# Generated by FakeRAM 2.0
VERSION 5.7 ;
BUSBITCHARS "[]" ;
PROPERTYDEFINITIONS
  MACRO width INTEGER ;
  MACRO depth INTEGER ;
  MACRO banks INTEGER ;
END PROPERTYDEFINITIONS
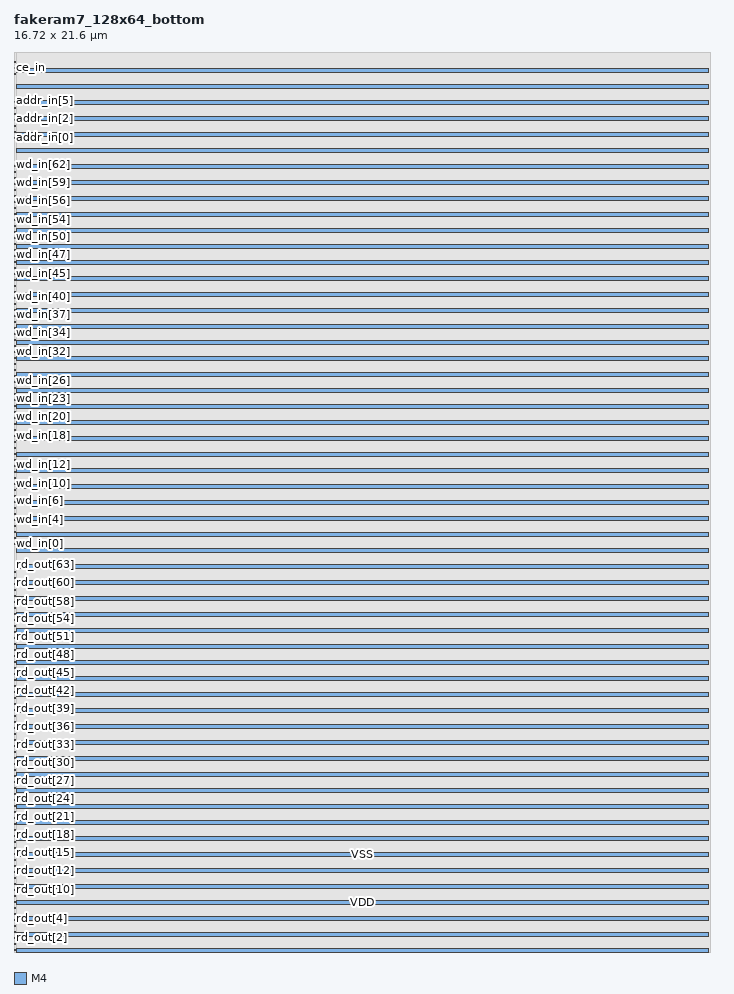
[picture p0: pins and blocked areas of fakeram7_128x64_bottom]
MACRO fakeram7_128x64_bottom
  PROPERTY width 64 ;
  PROPERTY depth 128 ;
  PROPERTY banks 2 ;
  FOREIGN fakeram7_128x64_bottom 0 0 ;
  SYMMETRY X Y R90 ;
  SIZE 16.720 BY 21.600 ;
  CLASS BLOCK ;
  PIN rd_out[0]
    DIRECTION OUTPUT ;
    USE SIGNAL ;
    SHAPE ABUTMENT ;
    PORT
      LAYER M4 ;
      RECT 0.000 0.039 0.024 0.063 ;
    END
  END rd_out[0]
  PIN rd_out[1]
    DIRECTION OUTPUT ;
    USE SIGNAL ;
    SHAPE ABUTMENT ;
    PORT
      LAYER M4 ;
      RECT 0.000 0.183 0.024 0.207 ;
    END
  END rd_out[1]
  PIN rd_out[2]
    DIRECTION OUTPUT ;
    USE SIGNAL ;
    SHAPE ABUTMENT ;
    PORT
      LAYER M4 ;
      RECT 0.000 0.327 0.024 0.351 ;
    END
  END rd_out[2]
  PIN rd_out[3]
    DIRECTION OUTPUT ;
    USE SIGNAL ;
    SHAPE ABUTMENT ;
    PORT
      LAYER M4 ;
      RECT 0.000 0.471 0.024 0.495 ;
    END
  END rd_out[3]
  PIN rd_out[4]
    DIRECTION OUTPUT ;
    USE SIGNAL ;
    SHAPE ABUTMENT ;
    PORT
      LAYER M4 ;
      RECT 0.000 0.615 0.024 0.639 ;
    END
  END rd_out[4]
  PIN rd_out[5]
    DIRECTION OUTPUT ;
    USE SIGNAL ;
    SHAPE ABUTMENT ;
    PORT
      LAYER M4 ;
      RECT 0.000 0.759 0.024 0.783 ;
    END
  END rd_out[5]
  PIN rd_out[6]
    DIRECTION OUTPUT ;
    USE SIGNAL ;
    SHAPE ABUTMENT ;
    PORT
      LAYER M4 ;
      RECT 0.000 0.903 0.024 0.927 ;
    END
  END rd_out[6]
  PIN rd_out[7]
    DIRECTION OUTPUT ;
    USE SIGNAL ;
    SHAPE ABUTMENT ;
    PORT
      LAYER M4 ;
      RECT 0.000 1.047 0.024 1.071 ;
    END
  END rd_out[7]
  PIN rd_out[8]
    DIRECTION OUTPUT ;
    USE SIGNAL ;
    SHAPE ABUTMENT ;
    PORT
      LAYER M4 ;
      RECT 0.000 1.191 0.024 1.215 ;
    END
  END rd_out[8]
  PIN rd_out[9]
    DIRECTION OUTPUT ;
    USE SIGNAL ;
    SHAPE ABUTMENT ;
    PORT
      LAYER M4 ;
      RECT 0.000 1.335 0.024 1.359 ;
    END
  END rd_out[9]
  PIN rd_out[10]
    DIRECTION OUTPUT ;
    USE SIGNAL ;
    SHAPE ABUTMENT ;
    PORT
      LAYER M4 ;
      RECT 0.000 1.479 0.024 1.503 ;
    END
  END rd_out[10]
  PIN rd_out[11]
    DIRECTION OUTPUT ;
    USE SIGNAL ;
    SHAPE ABUTMENT ;
    PORT
      LAYER M4 ;
      RECT 0.000 1.623 0.024 1.647 ;
    END
  END rd_out[11]
  PIN rd_out[12]
    DIRECTION OUTPUT ;
    USE SIGNAL ;
    SHAPE ABUTMENT ;
    PORT
      LAYER M4 ;
      RECT 0.000 1.767 0.024 1.791 ;
    END
  END rd_out[12]
  PIN rd_out[13]
    DIRECTION OUTPUT ;
    USE SIGNAL ;
    SHAPE ABUTMENT ;
    PORT
      LAYER M4 ;
      RECT 0.000 1.911 0.024 1.935 ;
    END
  END rd_out[13]
  PIN rd_out[14]
    DIRECTION OUTPUT ;
    USE SIGNAL ;
    SHAPE ABUTMENT ;
    PORT
      LAYER M4 ;
      RECT 0.000 2.055 0.024 2.079 ;
    END
  END rd_out[14]
  PIN rd_out[15]
    DIRECTION OUTPUT ;
    USE SIGNAL ;
    SHAPE ABUTMENT ;
    PORT
      LAYER M4 ;
      RECT 0.000 2.199 0.024 2.223 ;
    END
  END rd_out[15]
  PIN rd_out[16]
    DIRECTION OUTPUT ;
    USE SIGNAL ;
    SHAPE ABUTMENT ;
    PORT
      LAYER M4 ;
      RECT 0.000 2.343 0.024 2.367 ;
    END
  END rd_out[16]
  PIN rd_out[17]
    DIRECTION OUTPUT ;
    USE SIGNAL ;
    SHAPE ABUTMENT ;
    PORT
      LAYER M4 ;
      RECT 0.000 2.487 0.024 2.511 ;
    END
  END rd_out[17]
  PIN rd_out[18]
    DIRECTION OUTPUT ;
    USE SIGNAL ;
    SHAPE ABUTMENT ;
    PORT
      LAYER M4 ;
      RECT 0.000 2.631 0.024 2.655 ;
    END
  END rd_out[18]
  PIN rd_out[19]
    DIRECTION OUTPUT ;
    USE SIGNAL ;
    SHAPE ABUTMENT ;
    PORT
      LAYER M4 ;
      RECT 0.000 2.775 0.024 2.799 ;
    END
  END rd_out[19]
  PIN rd_out[20]
    DIRECTION OUTPUT ;
    USE SIGNAL ;
    SHAPE ABUTMENT ;
    PORT
      LAYER M4 ;
      RECT 0.000 2.919 0.024 2.943 ;
    END
  END rd_out[20]
  PIN rd_out[21]
    DIRECTION OUTPUT ;
    USE SIGNAL ;
    SHAPE ABUTMENT ;
    PORT
      LAYER M4 ;
      RECT 0.000 3.063 0.024 3.087 ;
    END
  END rd_out[21]
  PIN rd_out[22]
    DIRECTION OUTPUT ;
    USE SIGNAL ;
    SHAPE ABUTMENT ;
    PORT
      LAYER M4 ;
      RECT 0.000 3.207 0.024 3.231 ;
    END
  END rd_out[22]
  PIN rd_out[23]
    DIRECTION OUTPUT ;
    USE SIGNAL ;
    SHAPE ABUTMENT ;
    PORT
      LAYER M4 ;
      RECT 0.000 3.351 0.024 3.375 ;
    END
  END rd_out[23]
  PIN rd_out[24]
    DIRECTION OUTPUT ;
    USE SIGNAL ;
    SHAPE ABUTMENT ;
    PORT
      LAYER M4 ;
      RECT 0.000 3.495 0.024 3.519 ;
    END
  END rd_out[24]
  PIN rd_out[25]
    DIRECTION OUTPUT ;
    USE SIGNAL ;
    SHAPE ABUTMENT ;
    PORT
      LAYER M4 ;
      RECT 0.000 3.639 0.024 3.663 ;
    END
  END rd_out[25]
  PIN rd_out[26]
    DIRECTION OUTPUT ;
    USE SIGNAL ;
    SHAPE ABUTMENT ;
    PORT
      LAYER M4 ;
      RECT 0.000 3.783 0.024 3.807 ;
    END
  END rd_out[26]
  PIN rd_out[27]
    DIRECTION OUTPUT ;
    USE SIGNAL ;
    SHAPE ABUTMENT ;
    PORT
      LAYER M4 ;
      RECT 0.000 3.927 0.024 3.951 ;
    END
  END rd_out[27]
  PIN rd_out[28]
    DIRECTION OUTPUT ;
    USE SIGNAL ;
    SHAPE ABUTMENT ;
    PORT
      LAYER M4 ;
      RECT 0.000 4.071 0.024 4.095 ;
    END
  END rd_out[28]
  PIN rd_out[29]
    DIRECTION OUTPUT ;
    USE SIGNAL ;
    SHAPE ABUTMENT ;
    PORT
      LAYER M4 ;
      RECT 0.000 4.215 0.024 4.239 ;
    END
  END rd_out[29]
  PIN rd_out[30]
    DIRECTION OUTPUT ;
    USE SIGNAL ;
    SHAPE ABUTMENT ;
    PORT
      LAYER M4 ;
      RECT 0.000 4.359 0.024 4.383 ;
    END
  END rd_out[30]
  PIN rd_out[31]
    DIRECTION OUTPUT ;
    USE SIGNAL ;
    SHAPE ABUTMENT ;
    PORT
      LAYER M4 ;
      RECT 0.000 4.503 0.024 4.527 ;
    END
  END rd_out[31]
  PIN rd_out[32]
    DIRECTION OUTPUT ;
    USE SIGNAL ;
    SHAPE ABUTMENT ;
    PORT
      LAYER M4 ;
      RECT 0.000 4.647 0.024 4.671 ;
    END
  END rd_out[32]
  PIN rd_out[33]
    DIRECTION OUTPUT ;
    USE SIGNAL ;
    SHAPE ABUTMENT ;
    PORT
      LAYER M4 ;
      RECT 0.000 4.791 0.024 4.815 ;
    END
  END rd_out[33]
  PIN rd_out[34]
    DIRECTION OUTPUT ;
    USE SIGNAL ;
    SHAPE ABUTMENT ;
    PORT
      LAYER M4 ;
      RECT 0.000 4.935 0.024 4.959 ;
    END
  END rd_out[34]
  PIN rd_out[35]
    DIRECTION OUTPUT ;
    USE SIGNAL ;
    SHAPE ABUTMENT ;
    PORT
      LAYER M4 ;
      RECT 0.000 5.079 0.024 5.103 ;
    END
  END rd_out[35]
  PIN rd_out[36]
    DIRECTION OUTPUT ;
    USE SIGNAL ;
    SHAPE ABUTMENT ;
    PORT
      LAYER M4 ;
      RECT 0.000 5.223 0.024 5.247 ;
    END
  END rd_out[36]
  PIN rd_out[37]
    DIRECTION OUTPUT ;
    USE SIGNAL ;
    SHAPE ABUTMENT ;
    PORT
      LAYER M4 ;
      RECT 0.000 5.367 0.024 5.391 ;
    END
  END rd_out[37]
  PIN rd_out[38]
    DIRECTION OUTPUT ;
    USE SIGNAL ;
    SHAPE ABUTMENT ;
    PORT
      LAYER M4 ;
      RECT 0.000 5.511 0.024 5.535 ;
    END
  END rd_out[38]
  PIN rd_out[39]
    DIRECTION OUTPUT ;
    USE SIGNAL ;
    SHAPE ABUTMENT ;
    PORT
      LAYER M4 ;
      RECT 0.000 5.655 0.024 5.679 ;
    END
  END rd_out[39]
  PIN rd_out[40]
    DIRECTION OUTPUT ;
    USE SIGNAL ;
    SHAPE ABUTMENT ;
    PORT
      LAYER M4 ;
      RECT 0.000 5.799 0.024 5.823 ;
    END
  END rd_out[40]
  PIN rd_out[41]
    DIRECTION OUTPUT ;
    USE SIGNAL ;
    SHAPE ABUTMENT ;
    PORT
      LAYER M4 ;
      RECT 0.000 5.943 0.024 5.967 ;
    END
  END rd_out[41]
  PIN rd_out[42]
    DIRECTION OUTPUT ;
    USE SIGNAL ;
    SHAPE ABUTMENT ;
    PORT
      LAYER M4 ;
      RECT 0.000 6.087 0.024 6.111 ;
    END
  END rd_out[42]
  PIN rd_out[43]
    DIRECTION OUTPUT ;
    USE SIGNAL ;
    SHAPE ABUTMENT ;
    PORT
      LAYER M4 ;
      RECT 0.000 6.231 0.024 6.255 ;
    END
  END rd_out[43]
  PIN rd_out[44]
    DIRECTION OUTPUT ;
    USE SIGNAL ;
    SHAPE ABUTMENT ;
    PORT
      LAYER M4 ;
      RECT 0.000 6.375 0.024 6.399 ;
    END
  END rd_out[44]
  PIN rd_out[45]
    DIRECTION OUTPUT ;
    USE SIGNAL ;
    SHAPE ABUTMENT ;
    PORT
      LAYER M4 ;
      RECT 0.000 6.519 0.024 6.543 ;
    END
  END rd_out[45]
  PIN rd_out[46]
    DIRECTION OUTPUT ;
    USE SIGNAL ;
    SHAPE ABUTMENT ;
    PORT
      LAYER M4 ;
      RECT 0.000 6.663 0.024 6.687 ;
    END
  END rd_out[46]
  PIN rd_out[47]
    DIRECTION OUTPUT ;
    USE SIGNAL ;
    SHAPE ABUTMENT ;
    PORT
      LAYER M4 ;
      RECT 0.000 6.807 0.024 6.831 ;
    END
  END rd_out[47]
  PIN rd_out[48]
    DIRECTION OUTPUT ;
    USE SIGNAL ;
    SHAPE ABUTMENT ;
    PORT
      LAYER M4 ;
      RECT 0.000 6.951 0.024 6.975 ;
    END
  END rd_out[48]
  PIN rd_out[49]
    DIRECTION OUTPUT ;
    USE SIGNAL ;
    SHAPE ABUTMENT ;
    PORT
      LAYER M4 ;
      RECT 0.000 7.095 0.024 7.119 ;
    END
  END rd_out[49]
  PIN rd_out[50]
    DIRECTION OUTPUT ;
    USE SIGNAL ;
    SHAPE ABUTMENT ;
    PORT
      LAYER M4 ;
      RECT 0.000 7.239 0.024 7.263 ;
    END
  END rd_out[50]
  PIN rd_out[51]
    DIRECTION OUTPUT ;
    USE SIGNAL ;
    SHAPE ABUTMENT ;
    PORT
      LAYER M4 ;
      RECT 0.000 7.383 0.024 7.407 ;
    END
  END rd_out[51]
  PIN rd_out[52]
    DIRECTION OUTPUT ;
    USE SIGNAL ;
    SHAPE ABUTMENT ;
    PORT
      LAYER M4 ;
      RECT 0.000 7.527 0.024 7.551 ;
    END
  END rd_out[52]
  PIN rd_out[53]
    DIRECTION OUTPUT ;
    USE SIGNAL ;
    SHAPE ABUTMENT ;
    PORT
      LAYER M4 ;
      RECT 0.000 7.671 0.024 7.695 ;
    END
  END rd_out[53]
  PIN rd_out[54]
    DIRECTION OUTPUT ;
    USE SIGNAL ;
    SHAPE ABUTMENT ;
    PORT
      LAYER M4 ;
      RECT 0.000 7.815 0.024 7.839 ;
    END
  END rd_out[54]
  PIN rd_out[55]
    DIRECTION OUTPUT ;
    USE SIGNAL ;
    SHAPE ABUTMENT ;
    PORT
      LAYER M4 ;
      RECT 0.000 7.959 0.024 7.983 ;
    END
  END rd_out[55]
  PIN rd_out[56]
    DIRECTION OUTPUT ;
    USE SIGNAL ;
    SHAPE ABUTMENT ;
    PORT
      LAYER M4 ;
      RECT 0.000 8.103 0.024 8.127 ;
    END
  END rd_out[56]
  PIN rd_out[57]
    DIRECTION OUTPUT ;
    USE SIGNAL ;
    SHAPE ABUTMENT ;
    PORT
      LAYER M4 ;
      RECT 0.000 8.247 0.024 8.271 ;
    END
  END rd_out[57]
  PIN rd_out[58]
    DIRECTION OUTPUT ;
    USE SIGNAL ;
    SHAPE ABUTMENT ;
    PORT
      LAYER M4 ;
      RECT 0.000 8.391 0.024 8.415 ;
    END
  END rd_out[58]
  PIN rd_out[59]
    DIRECTION OUTPUT ;
    USE SIGNAL ;
    SHAPE ABUTMENT ;
    PORT
      LAYER M4 ;
      RECT 0.000 8.535 0.024 8.559 ;
    END
  END rd_out[59]
  PIN rd_out[60]
    DIRECTION OUTPUT ;
    USE SIGNAL ;
    SHAPE ABUTMENT ;
    PORT
      LAYER M4 ;
      RECT 0.000 8.679 0.024 8.703 ;
    END
  END rd_out[60]
  PIN rd_out[61]
    DIRECTION OUTPUT ;
    USE SIGNAL ;
    SHAPE ABUTMENT ;
    PORT
      LAYER M4 ;
      RECT 0.000 8.823 0.024 8.847 ;
    END
  END rd_out[61]
  PIN rd_out[62]
    DIRECTION OUTPUT ;
    USE SIGNAL ;
    SHAPE ABUTMENT ;
    PORT
      LAYER M4 ;
      RECT 0.000 8.967 0.024 8.991 ;
    END
  END rd_out[62]
  PIN rd_out[63]
    DIRECTION OUTPUT ;
    USE SIGNAL ;
    SHAPE ABUTMENT ;
    PORT
      LAYER M4 ;
      RECT 0.000 9.111 0.024 9.135 ;
    END
  END rd_out[63]
  PIN wd_in[0]
    DIRECTION INPUT ;
    USE SIGNAL ;
    SHAPE ABUTMENT ;
    PORT
      LAYER M4 ;
      RECT 0.000 9.783 0.024 9.807 ;
    END
  END wd_in[0]
  PIN wd_in[1]
    DIRECTION INPUT ;
    USE SIGNAL ;
    SHAPE ABUTMENT ;
    PORT
      LAYER M4 ;
      RECT 0.000 9.927 0.024 9.951 ;
    END
  END wd_in[1]
  PIN wd_in[2]
    DIRECTION INPUT ;
    USE SIGNAL ;
    SHAPE ABUTMENT ;
    PORT
      LAYER M4 ;
      RECT 0.000 10.071 0.024 10.095 ;
    END
  END wd_in[2]
  PIN wd_in[3]
    DIRECTION INPUT ;
    USE SIGNAL ;
    SHAPE ABUTMENT ;
    PORT
      LAYER M4 ;
      RECT 0.000 10.215 0.024 10.239 ;
    END
  END wd_in[3]
  PIN wd_in[4]
    DIRECTION INPUT ;
    USE SIGNAL ;
    SHAPE ABUTMENT ;
    PORT
      LAYER M4 ;
      RECT 0.000 10.359 0.024 10.383 ;
    END
  END wd_in[4]
  PIN wd_in[5]
    DIRECTION INPUT ;
    USE SIGNAL ;
    SHAPE ABUTMENT ;
    PORT
      LAYER M4 ;
      RECT 0.000 10.503 0.024 10.527 ;
    END
  END wd_in[5]
  PIN wd_in[6]
    DIRECTION INPUT ;
    USE SIGNAL ;
    SHAPE ABUTMENT ;
    PORT
      LAYER M4 ;
      RECT 0.000 10.647 0.024 10.671 ;
    END
  END wd_in[6]
  PIN wd_in[7]
    DIRECTION INPUT ;
    USE SIGNAL ;
    SHAPE ABUTMENT ;
    PORT
      LAYER M4 ;
      RECT 0.000 10.791 0.024 10.815 ;
    END
  END wd_in[7]
  PIN wd_in[8]
    DIRECTION INPUT ;
    USE SIGNAL ;
    SHAPE ABUTMENT ;
    PORT
      LAYER M4 ;
      RECT 0.000 10.935 0.024 10.959 ;
    END
  END wd_in[8]
  PIN wd_in[9]
    DIRECTION INPUT ;
    USE SIGNAL ;
    SHAPE ABUTMENT ;
    PORT
      LAYER M4 ;
      RECT 0.000 11.079 0.024 11.103 ;
    END
  END wd_in[9]
  PIN wd_in[10]
    DIRECTION INPUT ;
    USE SIGNAL ;
    SHAPE ABUTMENT ;
    PORT
      LAYER M4 ;
      RECT 0.000 11.223 0.024 11.247 ;
    END
  END wd_in[10]
  PIN wd_in[11]
    DIRECTION INPUT ;
    USE SIGNAL ;
    SHAPE ABUTMENT ;
    PORT
      LAYER M4 ;
      RECT 0.000 11.367 0.024 11.391 ;
    END
  END wd_in[11]
  PIN wd_in[12]
    DIRECTION INPUT ;
    USE SIGNAL ;
    SHAPE ABUTMENT ;
    PORT
      LAYER M4 ;
      RECT 0.000 11.511 0.024 11.535 ;
    END
  END wd_in[12]
  PIN wd_in[13]
    DIRECTION INPUT ;
    USE SIGNAL ;
    SHAPE ABUTMENT ;
    PORT
      LAYER M4 ;
      RECT 0.000 11.655 0.024 11.679 ;
    END
  END wd_in[13]
  PIN wd_in[14]
    DIRECTION INPUT ;
    USE SIGNAL ;
    SHAPE ABUTMENT ;
    PORT
      LAYER M4 ;
      RECT 0.000 11.799 0.024 11.823 ;
    END
  END wd_in[14]
  PIN wd_in[15]
    DIRECTION INPUT ;
    USE SIGNAL ;
    SHAPE ABUTMENT ;
    PORT
      LAYER M4 ;
      RECT 0.000 11.943 0.024 11.967 ;
    END
  END wd_in[15]
  PIN wd_in[16]
    DIRECTION INPUT ;
    USE SIGNAL ;
    SHAPE ABUTMENT ;
    PORT
      LAYER M4 ;
      RECT 0.000 12.087 0.024 12.111 ;
    END
  END wd_in[16]
  PIN wd_in[17]
    DIRECTION INPUT ;
    USE SIGNAL ;
    SHAPE ABUTMENT ;
    PORT
      LAYER M4 ;
      RECT 0.000 12.231 0.024 12.255 ;
    END
  END wd_in[17]
  PIN wd_in[18]
    DIRECTION INPUT ;
    USE SIGNAL ;
    SHAPE ABUTMENT ;
    PORT
      LAYER M4 ;
      RECT 0.000 12.375 0.024 12.399 ;
    END
  END wd_in[18]
  PIN wd_in[19]
    DIRECTION INPUT ;
    USE SIGNAL ;
    SHAPE ABUTMENT ;
    PORT
      LAYER M4 ;
      RECT 0.000 12.519 0.024 12.543 ;
    END
  END wd_in[19]
  PIN wd_in[20]
    DIRECTION INPUT ;
    USE SIGNAL ;
    SHAPE ABUTMENT ;
    PORT
      LAYER M4 ;
      RECT 0.000 12.663 0.024 12.687 ;
    END
  END wd_in[20]
  PIN wd_in[21]
    DIRECTION INPUT ;
    USE SIGNAL ;
    SHAPE ABUTMENT ;
    PORT
      LAYER M4 ;
      RECT 0.000 12.807 0.024 12.831 ;
    END
  END wd_in[21]
  PIN wd_in[22]
    DIRECTION INPUT ;
    USE SIGNAL ;
    SHAPE ABUTMENT ;
    PORT
      LAYER M4 ;
      RECT 0.000 12.951 0.024 12.975 ;
    END
  END wd_in[22]
  PIN wd_in[23]
    DIRECTION INPUT ;
    USE SIGNAL ;
    SHAPE ABUTMENT ;
    PORT
      LAYER M4 ;
      RECT 0.000 13.095 0.024 13.119 ;
    END
  END wd_in[23]
  PIN wd_in[24]
    DIRECTION INPUT ;
    USE SIGNAL ;
    SHAPE ABUTMENT ;
    PORT
      LAYER M4 ;
      RECT 0.000 13.239 0.024 13.263 ;
    END
  END wd_in[24]
  PIN wd_in[25]
    DIRECTION INPUT ;
    USE SIGNAL ;
    SHAPE ABUTMENT ;
    PORT
      LAYER M4 ;
      RECT 0.000 13.383 0.024 13.407 ;
    END
  END wd_in[25]
  PIN wd_in[26]
    DIRECTION INPUT ;
    USE SIGNAL ;
    SHAPE ABUTMENT ;
    PORT
      LAYER M4 ;
      RECT 0.000 13.527 0.024 13.551 ;
    END
  END wd_in[26]
  PIN wd_in[27]
    DIRECTION INPUT ;
    USE SIGNAL ;
    SHAPE ABUTMENT ;
    PORT
      LAYER M4 ;
      RECT 0.000 13.671 0.024 13.695 ;
    END
  END wd_in[27]
  PIN wd_in[28]
    DIRECTION INPUT ;
    USE SIGNAL ;
    SHAPE ABUTMENT ;
    PORT
      LAYER M4 ;
      RECT 0.000 13.815 0.024 13.839 ;
    END
  END wd_in[28]
  PIN wd_in[29]
    DIRECTION INPUT ;
    USE SIGNAL ;
    SHAPE ABUTMENT ;
    PORT
      LAYER M4 ;
      RECT 0.000 13.959 0.024 13.983 ;
    END
  END wd_in[29]
  PIN wd_in[30]
    DIRECTION INPUT ;
    USE SIGNAL ;
    SHAPE ABUTMENT ;
    PORT
      LAYER M4 ;
      RECT 0.000 14.103 0.024 14.127 ;
    END
  END wd_in[30]
  PIN wd_in[31]
    DIRECTION INPUT ;
    USE SIGNAL ;
    SHAPE ABUTMENT ;
    PORT
      LAYER M4 ;
      RECT 0.000 14.247 0.024 14.271 ;
    END
  END wd_in[31]
  PIN wd_in[32]
    DIRECTION INPUT ;
    USE SIGNAL ;
    SHAPE ABUTMENT ;
    PORT
      LAYER M4 ;
      RECT 0.000 14.391 0.024 14.415 ;
    END
  END wd_in[32]
  PIN wd_in[33]
    DIRECTION INPUT ;
    USE SIGNAL ;
    SHAPE ABUTMENT ;
    PORT
      LAYER M4 ;
      RECT 0.000 14.535 0.024 14.559 ;
    END
  END wd_in[33]
  PIN wd_in[34]
    DIRECTION INPUT ;
    USE SIGNAL ;
    SHAPE ABUTMENT ;
    PORT
      LAYER M4 ;
      RECT 0.000 14.679 0.024 14.703 ;
    END
  END wd_in[34]
  PIN wd_in[35]
    DIRECTION INPUT ;
    USE SIGNAL ;
    SHAPE ABUTMENT ;
    PORT
      LAYER M4 ;
      RECT 0.000 14.823 0.024 14.847 ;
    END
  END wd_in[35]
  PIN wd_in[36]
    DIRECTION INPUT ;
    USE SIGNAL ;
    SHAPE ABUTMENT ;
    PORT
      LAYER M4 ;
      RECT 0.000 14.967 0.024 14.991 ;
    END
  END wd_in[36]
  PIN wd_in[37]
    DIRECTION INPUT ;
    USE SIGNAL ;
    SHAPE ABUTMENT ;
    PORT
      LAYER M4 ;
      RECT 0.000 15.111 0.024 15.135 ;
    END
  END wd_in[37]
  PIN wd_in[38]
    DIRECTION INPUT ;
    USE SIGNAL ;
    SHAPE ABUTMENT ;
    PORT
      LAYER M4 ;
      RECT 0.000 15.255 0.024 15.279 ;
    END
  END wd_in[38]
  PIN wd_in[39]
    DIRECTION INPUT ;
    USE SIGNAL ;
    SHAPE ABUTMENT ;
    PORT
      LAYER M4 ;
      RECT 0.000 15.399 0.024 15.423 ;
    END
  END wd_in[39]
  PIN wd_in[40]
    DIRECTION INPUT ;
    USE SIGNAL ;
    SHAPE ABUTMENT ;
    PORT
      LAYER M4 ;
      RECT 0.000 15.543 0.024 15.567 ;
    END
  END wd_in[40]
  PIN wd_in[41]
    DIRECTION INPUT ;
    USE SIGNAL ;
    SHAPE ABUTMENT ;
    PORT
      LAYER M4 ;
      RECT 0.000 15.687 0.024 15.711 ;
    END
  END wd_in[41]
  PIN wd_in[42]
    DIRECTION INPUT ;
    USE SIGNAL ;
    SHAPE ABUTMENT ;
    PORT
      LAYER M4 ;
      RECT 0.000 15.831 0.024 15.855 ;
    END
  END wd_in[42]
  PIN wd_in[43]
    DIRECTION INPUT ;
    USE SIGNAL ;
    SHAPE ABUTMENT ;
    PORT
      LAYER M4 ;
      RECT 0.000 15.975 0.024 15.999 ;
    END
  END wd_in[43]
  PIN wd_in[44]
    DIRECTION INPUT ;
    USE SIGNAL ;
    SHAPE ABUTMENT ;
    PORT
      LAYER M4 ;
      RECT 0.000 16.119 0.024 16.143 ;
    END
  END wd_in[44]
  PIN wd_in[45]
    DIRECTION INPUT ;
    USE SIGNAL ;
    SHAPE ABUTMENT ;
    PORT
      LAYER M4 ;
      RECT 0.000 16.263 0.024 16.287 ;
    END
  END wd_in[45]
  PIN wd_in[46]
    DIRECTION INPUT ;
    USE SIGNAL ;
    SHAPE ABUTMENT ;
    PORT
      LAYER M4 ;
      RECT 0.000 16.407 0.024 16.431 ;
    END
  END wd_in[46]
  PIN wd_in[47]
    DIRECTION INPUT ;
    USE SIGNAL ;
    SHAPE ABUTMENT ;
    PORT
      LAYER M4 ;
      RECT 0.000 16.551 0.024 16.575 ;
    END
  END wd_in[47]
  PIN wd_in[48]
    DIRECTION INPUT ;
    USE SIGNAL ;
    SHAPE ABUTMENT ;
    PORT
      LAYER M4 ;
      RECT 0.000 16.695 0.024 16.719 ;
    END
  END wd_in[48]
  PIN wd_in[49]
    DIRECTION INPUT ;
    USE SIGNAL ;
    SHAPE ABUTMENT ;
    PORT
      LAYER M4 ;
      RECT 0.000 16.839 0.024 16.863 ;
    END
  END wd_in[49]
  PIN wd_in[50]
    DIRECTION INPUT ;
    USE SIGNAL ;
    SHAPE ABUTMENT ;
    PORT
      LAYER M4 ;
      RECT 0.000 16.983 0.024 17.007 ;
    END
  END wd_in[50]
  PIN wd_in[51]
    DIRECTION INPUT ;
    USE SIGNAL ;
    SHAPE ABUTMENT ;
    PORT
      LAYER M4 ;
      RECT 0.000 17.127 0.024 17.151 ;
    END
  END wd_in[51]
  PIN wd_in[52]
    DIRECTION INPUT ;
    USE SIGNAL ;
    SHAPE ABUTMENT ;
    PORT
      LAYER M4 ;
      RECT 0.000 17.271 0.024 17.295 ;
    END
  END wd_in[52]
  PIN wd_in[53]
    DIRECTION INPUT ;
    USE SIGNAL ;
    SHAPE ABUTMENT ;
    PORT
      LAYER M4 ;
      RECT 0.000 17.415 0.024 17.439 ;
    END
  END wd_in[53]
  PIN wd_in[54]
    DIRECTION INPUT ;
    USE SIGNAL ;
    SHAPE ABUTMENT ;
    PORT
      LAYER M4 ;
      RECT 0.000 17.559 0.024 17.583 ;
    END
  END wd_in[54]
  PIN wd_in[55]
    DIRECTION INPUT ;
    USE SIGNAL ;
    SHAPE ABUTMENT ;
    PORT
      LAYER M4 ;
      RECT 0.000 17.703 0.024 17.727 ;
    END
  END wd_in[55]
  PIN wd_in[56]
    DIRECTION INPUT ;
    USE SIGNAL ;
    SHAPE ABUTMENT ;
    PORT
      LAYER M4 ;
      RECT 0.000 17.847 0.024 17.871 ;
    END
  END wd_in[56]
  PIN wd_in[57]
    DIRECTION INPUT ;
    USE SIGNAL ;
    SHAPE ABUTMENT ;
    PORT
      LAYER M4 ;
      RECT 0.000 17.991 0.024 18.015 ;
    END
  END wd_in[57]
  PIN wd_in[58]
    DIRECTION INPUT ;
    USE SIGNAL ;
    SHAPE ABUTMENT ;
    PORT
      LAYER M4 ;
      RECT 0.000 18.135 0.024 18.159 ;
    END
  END wd_in[58]
  PIN wd_in[59]
    DIRECTION INPUT ;
    USE SIGNAL ;
    SHAPE ABUTMENT ;
    PORT
      LAYER M4 ;
      RECT 0.000 18.279 0.024 18.303 ;
    END
  END wd_in[59]
  PIN wd_in[60]
    DIRECTION INPUT ;
    USE SIGNAL ;
    SHAPE ABUTMENT ;
    PORT
      LAYER M4 ;
      RECT 0.000 18.423 0.024 18.447 ;
    END
  END wd_in[60]
  PIN wd_in[61]
    DIRECTION INPUT ;
    USE SIGNAL ;
    SHAPE ABUTMENT ;
    PORT
      LAYER M4 ;
      RECT 0.000 18.567 0.024 18.591 ;
    END
  END wd_in[61]
  PIN wd_in[62]
    DIRECTION INPUT ;
    USE SIGNAL ;
    SHAPE ABUTMENT ;
    PORT
      LAYER M4 ;
      RECT 0.000 18.711 0.024 18.735 ;
    END
  END wd_in[62]
  PIN wd_in[63]
    DIRECTION INPUT ;
    USE SIGNAL ;
    SHAPE ABUTMENT ;
    PORT
      LAYER M4 ;
      RECT 0.000 18.855 0.024 18.879 ;
    END
  END wd_in[63]
  PIN addr_in[0]
    DIRECTION INPUT ;
    USE SIGNAL ;
    SHAPE ABUTMENT ;
    PORT
      LAYER M4 ;
      RECT 0.000 19.527 0.024 19.551 ;
    END
  END addr_in[0]
  PIN addr_in[1]
    DIRECTION INPUT ;
    USE SIGNAL ;
    SHAPE ABUTMENT ;
    PORT
      LAYER M4 ;
      RECT 0.000 19.671 0.024 19.695 ;
    END
  END addr_in[1]
  PIN addr_in[2]
    DIRECTION INPUT ;
    USE SIGNAL ;
    SHAPE ABUTMENT ;
    PORT
      LAYER M4 ;
      RECT 0.000 19.815 0.024 19.839 ;
    END
  END addr_in[2]
  PIN addr_in[3]
    DIRECTION INPUT ;
    USE SIGNAL ;
    SHAPE ABUTMENT ;
    PORT
      LAYER M4 ;
      RECT 0.000 19.959 0.024 19.983 ;
    END
  END addr_in[3]
  PIN addr_in[4]
    DIRECTION INPUT ;
    USE SIGNAL ;
    SHAPE ABUTMENT ;
    PORT
      LAYER M4 ;
      RECT 0.000 20.103 0.024 20.127 ;
    END
  END addr_in[4]
  PIN addr_in[5]
    DIRECTION INPUT ;
    USE SIGNAL ;
    SHAPE ABUTMENT ;
    PORT
      LAYER M4 ;
      RECT 0.000 20.247 0.024 20.271 ;
    END
  END addr_in[5]
  PIN addr_in[6]
    DIRECTION INPUT ;
    USE SIGNAL ;
    SHAPE ABUTMENT ;
    PORT
      LAYER M4 ;
      RECT 0.000 20.391 0.024 20.415 ;
    END
  END addr_in[6]
  PIN we_in
    DIRECTION INPUT ;
    USE SIGNAL ;
    SHAPE ABUTMENT ;
    PORT
      LAYER M4 ;
      RECT 0.000 21.063 0.024 21.087 ;
    END
  END we_in
  PIN ce_in
    DIRECTION INPUT ;
    USE SIGNAL ;
    SHAPE ABUTMENT ;
    PORT
      LAYER M4 ;
      RECT 0.000 21.207 0.024 21.231 ;
    END
  END ce_in
  PIN clk
    DIRECTION INPUT ;
    USE SIGNAL ;
    SHAPE ABUTMENT ;
    PORT
      LAYER M4 ;
      RECT 0.000 21.351 0.024 21.375 ;
    END
  END clk
  PIN VSS
    DIRECTION INOUT ;
    USE GROUND ;
    PORT
      LAYER M4 ;
      RECT 0.048 0.000 16.672 0.096 ;
      RECT 0.048 0.768 16.672 0.864 ;
      RECT 0.048 1.536 16.672 1.632 ;
      RECT 0.048 2.304 16.672 2.400 ;
      RECT 0.048 3.072 16.672 3.168 ;
      RECT 0.048 3.840 16.672 3.936 ;
      RECT 0.048 4.608 16.672 4.704 ;
      RECT 0.048 5.376 16.672 5.472 ;
      RECT 0.048 6.144 16.672 6.240 ;
      RECT 0.048 6.912 16.672 7.008 ;
      RECT 0.048 7.680 16.672 7.776 ;
      RECT 0.048 8.448 16.672 8.544 ;
      RECT 0.048 9.216 16.672 9.312 ;
      RECT 0.048 9.984 16.672 10.080 ;
      RECT 0.048 10.752 16.672 10.848 ;
      RECT 0.048 11.520 16.672 11.616 ;
      RECT 0.048 12.288 16.672 12.384 ;
      RECT 0.048 13.056 16.672 13.152 ;
      RECT 0.048 13.824 16.672 13.920 ;
      RECT 0.048 14.592 16.672 14.688 ;
      RECT 0.048 15.360 16.672 15.456 ;
      RECT 0.048 16.128 16.672 16.224 ;
      RECT 0.048 16.896 16.672 16.992 ;
      RECT 0.048 17.664 16.672 17.760 ;
      RECT 0.048 18.432 16.672 18.528 ;
      RECT 0.048 19.200 16.672 19.296 ;
      RECT 0.048 19.968 16.672 20.064 ;
      RECT 0.048 20.736 16.672 20.832 ;
    END
  END VSS
  PIN VDD
    DIRECTION INOUT ;
    USE POWER ;
    PORT
      LAYER M4 ;
      RECT 0.048 0.384 16.672 0.480 ;
      RECT 0.048 1.152 16.672 1.248 ;
      RECT 0.048 1.920 16.672 2.016 ;
      RECT 0.048 2.688 16.672 2.784 ;
      RECT 0.048 3.456 16.672 3.552 ;
      RECT 0.048 4.224 16.672 4.320 ;
      RECT 0.048 4.992 16.672 5.088 ;
      RECT 0.048 5.760 16.672 5.856 ;
      RECT 0.048 6.528 16.672 6.624 ;
      RECT 0.048 7.296 16.672 7.392 ;
      RECT 0.048 8.064 16.672 8.160 ;
      RECT 0.048 8.832 16.672 8.928 ;
      RECT 0.048 9.600 16.672 9.696 ;
      RECT 0.048 10.368 16.672 10.464 ;
      RECT 0.048 11.136 16.672 11.232 ;
      RECT 0.048 11.904 16.672 12.000 ;
      RECT 0.048 12.672 16.672 12.768 ;
      RECT 0.048 13.440 16.672 13.536 ;
      RECT 0.048 14.208 16.672 14.304 ;
      RECT 0.048 14.976 16.672 15.072 ;
      RECT 0.048 15.744 16.672 15.840 ;
      RECT 0.048 16.512 16.672 16.608 ;
      RECT 0.048 17.280 16.672 17.376 ;
      RECT 0.048 18.048 16.672 18.144 ;
      RECT 0.048 18.816 16.672 18.912 ;
      RECT 0.048 19.584 16.672 19.680 ;
      RECT 0.048 20.352 16.672 20.448 ;
      RECT 0.048 21.120 16.672 21.216 ;
    END
  END VDD
  OBS
    LAYER M1 ;
    RECT 0 0 16.720 21.600 ;
    LAYER M2 ;
    RECT 0 0 16.720 21.600 ;
    LAYER M3 ;
    RECT 0.059 0.000 16.720 21.600 ;
    LAYER M4 ;
    RECT 0.059 0.000 16.720 21.600 ;
  END
END fakeram7_128x64_bottom

END LIBRARY
